One B-rep face of a CAD part: STEP entity #891.
In plain terms, the planar face has unit normal (1, 0, 0).
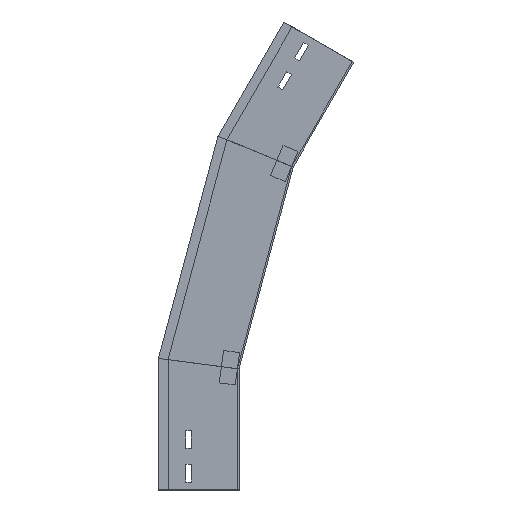
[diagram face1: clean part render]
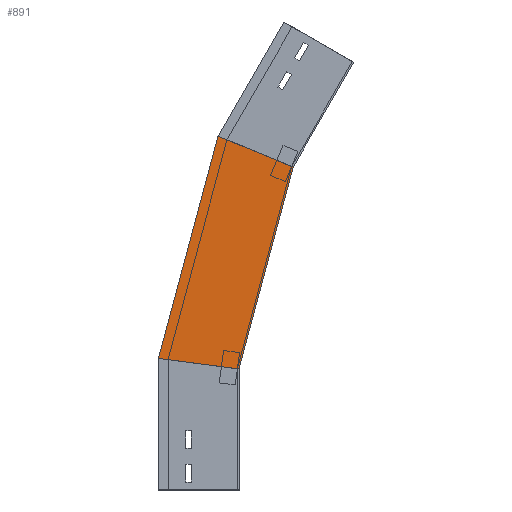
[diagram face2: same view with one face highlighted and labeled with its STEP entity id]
Its self-contained STEP definition (entity closure, numbers rounded to 3 decimals):
#48 = EDGE_CURVE ( 'NONE', #964, #228, #798, .T. ) ;
#52 = CARTESIAN_POINT ( 'NONE',  ( 0., 100.367, 161.797 ) ) ;
#124 = CARTESIAN_POINT ( 'NONE',  ( 0., 3.774, 135.915 ) ) ;
#139 = CARTESIAN_POINT ( 'NONE',  ( 0., -19.411, 147.444 ) ) ;
#210 = ORIENTED_EDGE ( 'NONE', *, *, #1110, .F. ) ;
#212 = CARTESIAN_POINT ( 'NONE',  ( 0., 3.774, 135.915 ) ) ;
#228 = VERTEX_POINT ( 'NONE', #546 ) ;
#244 = VERTEX_POINT ( 'NONE', #437 ) ;
#277 = CARTESIAN_POINT ( 'NONE',  ( 0., 100., 163.165 ) ) ;
#343 = DIRECTION ( 'NONE',  ( 0., -0.259, 0.966 ) ) ;
#363 = CARTESIAN_POINT ( 'NONE',  ( 0., -67.034, 400.175 ) ) ;
#391 = EDGE_CURVE ( 'NONE', #964, #244, #694, .T. ) ;
#437 = CARTESIAN_POINT ( 'NONE',  ( 0., 26.151, 438.773 ) ) ;
#546 = CARTESIAN_POINT ( 'NONE',  ( 0., 0., 150. ) ) ;
#550 = EDGE_LOOP ( 'NONE', ( #1349, #689, #210, #818 ) ) ;
#558 = DIRECTION ( 'NONE',  ( 0., -0.924, -0.383 ) ) ;
#591 = DIRECTION ( 'NONE',  ( 0., 0., -1. ) ) ;
#689 = ORIENTED_EDGE ( 'NONE', *, *, #1072, .T. ) ;
#694 = LINE ( 'NONE', #52, #1377 ) ;
#744 = LINE ( 'NONE', #1200, #1303 ) ;
#798 = LINE ( 'NONE', #139, #1496 ) ;
#802 = FACE_OUTER_BOUND ( 'NONE', #550, .T. ) ;
#818 = ORIENTED_EDGE ( 'NONE', *, *, #48, .F. ) ;
#891 = ADVANCED_FACE ( 'NONE', ( #802 ), #926, .T. ) ;
#926 = PLANE ( 'NONE',  #1350 ) ;
#931 = DIRECTION ( 'NONE',  ( 0., -0.259, 0.966 ) ) ;
#964 = VERTEX_POINT ( 'NONE', #277 ) ;
#1038 = VECTOR ( 'NONE', #343, 1000. ) ;
#1072 = EDGE_CURVE ( 'NONE', #244, #1495, #744, .T. ) ;
#1110 = EDGE_CURVE ( 'NONE', #228, #1495, #1214, .T. ) ;
#1161 = DIRECTION ( 'NONE',  ( 1., 0., 0. ) ) ;
#1200 = CARTESIAN_POINT ( 'NONE',  ( 0., -100.025, 386.509 ) ) ;
#1214 = LINE ( 'NONE', #212, #1038 ) ;
#1278 = DIRECTION ( 'NONE',  ( 0., -0.991, -0.131 ) ) ;
#1303 = VECTOR ( 'NONE', #558, 1000. ) ;
#1349 = ORIENTED_EDGE ( 'NONE', *, *, #391, .T. ) ;
#1350 = AXIS2_PLACEMENT_3D ( 'NONE', #124, #1161, #591 ) ;
#1377 = VECTOR ( 'NONE', #931, 1000. ) ;
#1495 = VERTEX_POINT ( 'NONE', #363 ) ;
#1496 = VECTOR ( 'NONE', #1278, 1000. ) ;
